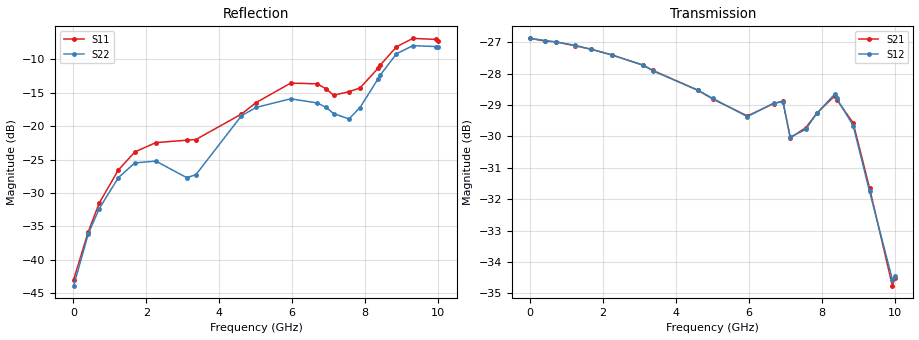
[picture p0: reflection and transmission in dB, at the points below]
! Device ID: PE43704
! Dir: z:\PE43704\PE43704_Char_1_20130516\PE43704\AMB\3p400V\26p00dB
! Serial: 14
! Insertion: A
! Impedance: 50 ohm
! Temp: Amb
! VDD: 3.400V
! Attenuation Step: 26.00dB
! IDD: 1.140731e-01mA
#  Hz  S  RI  R  50
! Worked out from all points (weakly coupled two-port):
!   401 points, 10 MHz to 10.01 GHz, reference 50 ohm
!   highest |S21| = -26.88 dB at 10 MHz (marker M1); lowest = -34.8 dB at 9.935 GHz (marker M2)
!   lowest |S11| = -43.0 dB at 10 MHz (marker M3), VSWR 1.01, Z = 50.7 + j0.0423 ohm
!   |S11| at or under -10 dB: start of sweep to 8.532 GHz
!   |S22| runs from -43.9 to -7.8 dB; largest |S21 - S12| = 0.00063
!   S11 on the Smith chart (normalised r, x): 10 MHz: 1.01, +0.00; 4.61 GHz: 0.80, +0.08; 8.41 GHz: 0.78, +0.48; 9.31 GHz: 0.51, +0.54; 10.01 GHz: 0.45, +0.33
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1e7  0.0071 0.000417  0.0453 -0.000165  0.0453 -0.000137  0.00639 0.00038
4.1e8  0.000817 0.0162  0.0446 -0.00483  0.0447 -0.0047  0.000932 0.0156
7.1e8  -0.012 0.0237  0.044 -0.008  0.044 -0.00794  -0.0106 0.0217
1.235e9  -0.0419 0.0213  0.042 -0.0134  0.0421 -0.0133  -0.0373 0.0175
1.685e9  -0.0636 0.00774  0.0398 -0.0176  0.0398 -0.0176  -0.053 0.00232
2.26e9  -0.0745 -0.0109  0.0363 -0.0223  0.0363 -0.0223  -0.0533 -0.0128
3.11e9  -0.077 -0.0154  0.0301 -0.0279  0.0302 -0.0278  -0.041 -0.0038
3.36e9  -0.0789 -0.00909  0.028 -0.029  0.028 -0.0289  -0.043 0.0051
4.61e9  -0.1116 0.0522  0.0184 -0.0326  0.0186 -0.0325  -0.1049 0.0576
5.01e9  -0.1307 0.0737  0.0163 -0.0324  0.0163 -0.0325  -0.1258 0.0569
5.96e9  -0.1812 0.1062  0.00995 -0.0326  0.01 -0.0325  -0.1507 0.0545
6.685e9  -0.1812 0.101  0.0069 -0.035  0.00672 -0.0351  -0.1393 0.0532
6.935e9  -0.1634 0.0969  0.00268 -0.0359  0.00257 -0.0358  -0.124 0.0609
7.135e9  -0.148 0.0846  0.0017 -0.0314  0.00173 -0.0315  -0.1042 0.0674
7.56e9  -0.1224 0.1335  0.00174 -0.0326  0.00176 -0.0324  -0.0683 0.0904
7.86e9  -0.0857 0.1729  0.000817 -0.0344  0.000742 -0.0344  -0.0591 0.1245
8.36e9  -0.0503 0.2675  -0.00768 -0.0359  -0.00737 -0.0362  -0.0729 0.2152
8.41e9  -0.0505 0.2809  -0.00841 -0.0352  -0.00824 -0.0354  -0.0793 0.2267
8.86e9  -0.0895 0.3824  -0.0151 -0.0296  -0.0148 -0.0294  -0.1381 0.3194
9.31e9  -0.1702 0.4208  -0.0149 -0.0215  -0.0145 -0.0214  -0.2227 0.3327
9.935e9  -0.302 0.3279  -0.00501 -0.0176  -0.00513 -0.018  -0.3444 0.1921
1.001e10  -0.3134 0.3026  -0.00395 -0.0184  -0.00403 -0.0185  -0.3532 0.1637
